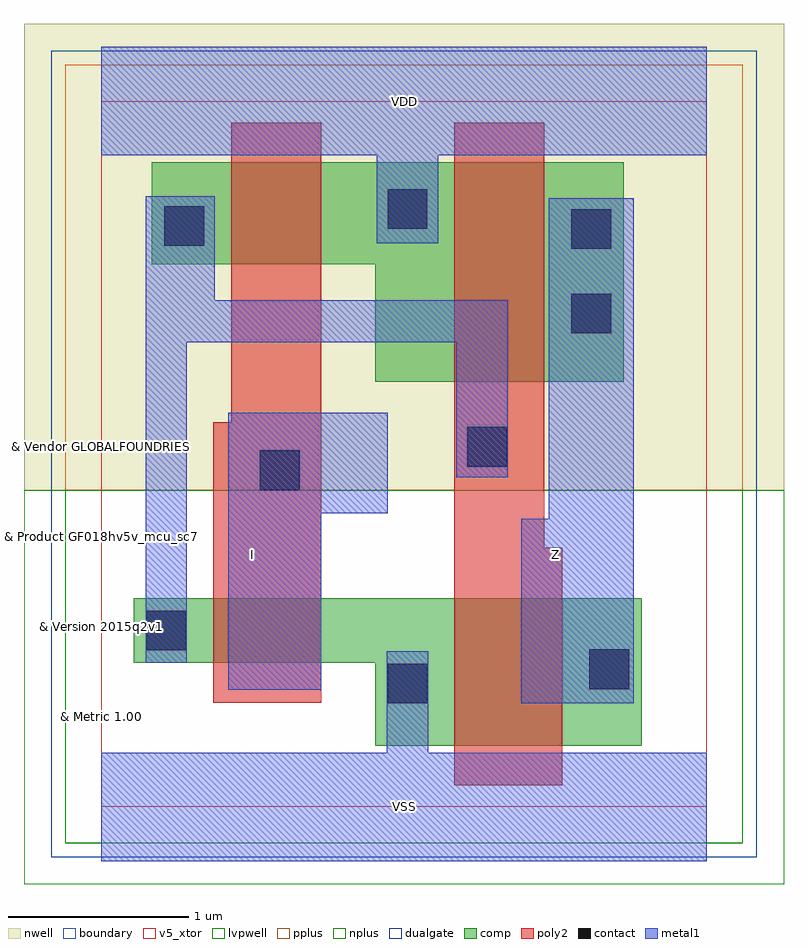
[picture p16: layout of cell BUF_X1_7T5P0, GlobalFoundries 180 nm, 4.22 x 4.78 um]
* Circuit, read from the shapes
.subckt BUF_X1_7T5P0 I VDD VSS Z
XM1 VSS I n1 VSUBS nfet_05v0 w=0.36u l=0.6u
XM2 Z n1 VSS VSUBS nfet_05v0 w=0.82u l=0.6u
XM3 VDD I n1 n2 pfet_05v0 w=0.565u l=0.5u
XM4 Z n1 VDD n2 pfet_05v0 w=1.22u l=0.5u
.ends

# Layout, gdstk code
import gdstk
lib = gdstk.Library(unit=1e-6, precision=1e-09)
def R(c, l, rs):  # rectangles x0, y0, x1, y1
    for r in rs: c.add(gdstk.rectangle(r[:2], r[2:], *l))
def P(c, l, *ps):  # polygons
    for p in ps: c.add(gdstk.Polygon(p, *l))
boundary = (0, 0)
nwell = (21, 0)
comp = (22, 0)
poly2 = (30, 0)
pplus = (31, 0)
nplus = (32, 0)
contact = (33, 0)
metal1 = (34, 0)
dualgate = (55, 0)
v5_xtor = (112, 1)
lvpwell = (204, 0)

buf_x1_7t5p0 = lib.new_cell('BUF_X1_7T5P0')
R(buf_x1_7t5p0, boundary, [(0,0,3.36,3.92)])
R(buf_x1_7t5p0, nwell, [(-0.43,1.76,3.79,4.35)])
P(buf_x1_7t5p0, comp, [(0.28,3.015),(1.52,3.015),(1.52,2.36),(2.9,2.36),(2.9,3.58),(0.28,3.58)],
  [(0.18,0.8),(1.52,0.8),(1.52,0.34),(3,0.34),(3,1.16),(0.18,1.16)])
P(buf_x1_7t5p0, poly2, [(0.62,0.58),(1.22,0.58),(1.22,3.8),(0.72,3.8),(0.72,2.135),(0.62,2.135)],
  [(1.96,0.12),(2.56,0.12),(2.56,1.44),(2.46,1.44),(2.46,3.8),(1.96,3.8)])
R(buf_x1_7t5p0, pplus, [(-0.2,1.76,3.56,4.12)])
R(buf_x1_7t5p0, nplus, [(-0.2,-0.2,3.56,1.76)])
R(buf_x1_7t5p0, contact, [(1.59,0.575,1.81,0.795), (2.71,0.655,2.93,0.875), (0.25,0.87,0.47,1.09), (0.88,1.76,1.1,1.98), (2.03,1.89,2.25,2.11), (2.61,2.63,2.83,2.85), (2.61,3.1,2.83,3.32), (0.35,3.115,0.57,3.335), (1.59,3.21,1.81,3.43)])
P(buf_x1_7t5p0, metal1, [(0.705,0.65),(1.22,0.65),(1.22,1.63),(1.59,1.63),(1.59,2.19),(0.705,2.19)],
  [(0.245,0.8),(0.475,0.8),(0.475,2.58),(1.97,2.58),(1.97,1.83),(2.255,1.83),(2.255,2.815),(0.63,2.815),(0.63,3.39),(0.245,3.39)],
  [(2.33,0.575),(2.955,0.575),(2.955,3.38),(2.485,3.38),(2.485,1.6),(2.33,1.6)],
  [(0,-0.3),(3.36,-0.3),(3.36,0.3),(1.815,0.3),(1.815,0.865),(1.585,0.865),(1.585,0.3),(0,0.3)],
  [(0,3.62),(1.53,3.62),(1.53,3.13),(1.87,3.13),(1.87,3.62),(3.36,3.62),(3.36,4.22),(0,4.22)])
R(buf_x1_7t5p0, dualgate, [(-0.28,-0.28,3.64,4.2)])
R(buf_x1_7t5p0, v5_xtor, [(0,0,3.36,3.92)])
R(buf_x1_7t5p0, lvpwell, [(-0.43,-0.43,3.79,1.76)])
buf_x1_7t5p0.add(gdstk.Label('VSS', (1.68,0), layer=34, texttype=10))
buf_x1_7t5p0.add(gdstk.Label('Z', (2.52,1.4), layer=34, texttype=10))
buf_x1_7t5p0.add(gdstk.Label('I', (0.84,1.4), layer=34, texttype=10))
buf_x1_7t5p0.add(gdstk.Label('VDD', (1.68,3.92), layer=34, texttype=10))
buf_x1_7t5p0.add(gdstk.Label('& Vendor GLOBALFOUNDRIES', (0,2), layer=63, texttype=63))
buf_x1_7t5p0.add(gdstk.Label('& Product GF018hv5v_mcu_sc7', (0,1.5), layer=63, texttype=63))
buf_x1_7t5p0.add(gdstk.Label('& Version 2015q2v1', (0,1), layer=63, texttype=63))
buf_x1_7t5p0.add(gdstk.Label('& Metric 1.00', (0,0.5), layer=63, texttype=63))

lib.write_gds('BUF_X1_7T5P0.gds')
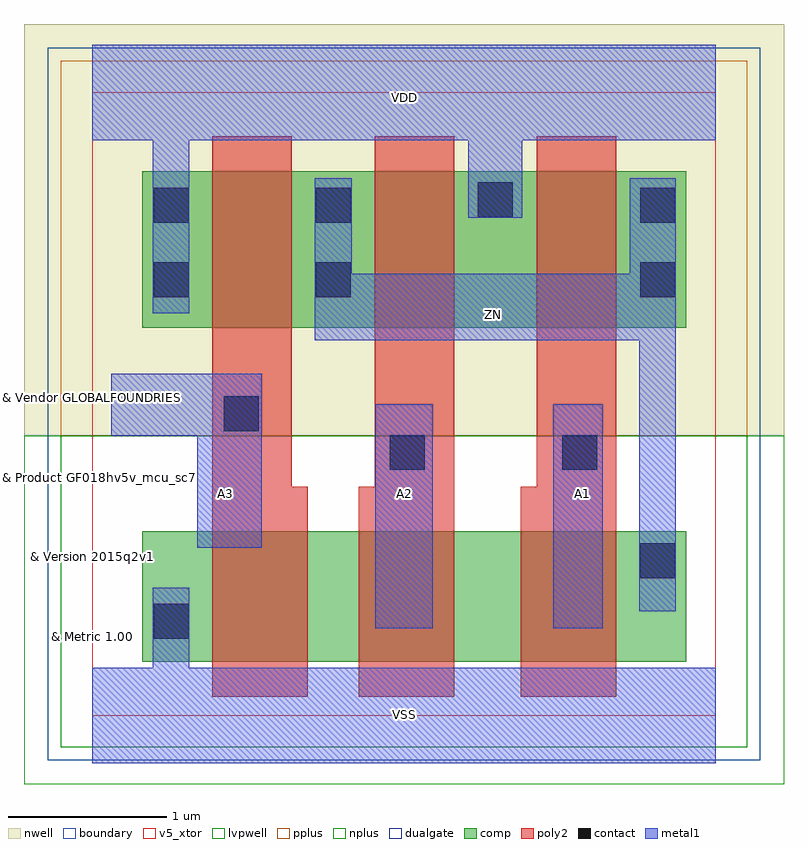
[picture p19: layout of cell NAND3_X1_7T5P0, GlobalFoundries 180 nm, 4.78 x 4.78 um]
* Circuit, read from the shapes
.subckt NAND3_X1_7T5P0 A1 A2 A3 VDD VSS ZN
XM1 n1 A3 VSS VSUBS nfet_05v0 w=0.82u l=0.6u
XM2 n2 A2 n1 VSUBS nfet_05v0 w=0.82u l=0.6u
XM3 ZN A1 n2 VSUBS nfet_05v0 w=0.82u l=0.6u
XM4 ZN A3 VDD n3 pfet_05v0 w=0.985u l=0.5u
XM5 VDD A2 ZN n3 pfet_05v0 w=0.985u l=0.5u
XM6 ZN A1 VDD n3 pfet_05v0 w=0.985u l=0.5u
.ends

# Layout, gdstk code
import gdstk
lib = gdstk.Library(unit=1e-6, precision=1e-09)
def R(c, l, rs):  # rectangles x0, y0, x1, y1
    for r in rs: c.add(gdstk.rectangle(r[:2], r[2:], *l))
def P(c, l, *ps):  # polygons
    for p in ps: c.add(gdstk.Polygon(p, *l))
boundary = (0, 0)
nwell = (21, 0)
comp = (22, 0)
poly2 = (30, 0)
pplus = (31, 0)
nplus = (32, 0)
contact = (33, 0)
metal1 = (34, 0)
dualgate = (55, 0)
v5_xtor = (112, 1)
lvpwell = (204, 0)

nand3_x1_7t5p0 = lib.new_cell('NAND3_X1_7T5P0')
R(nand3_x1_7t5p0, boundary, [(0,0,3.92,3.92)])
R(nand3_x1_7t5p0, nwell, [(-0.43,1.76,4.35,4.35)])
R(nand3_x1_7t5p0, comp, [(0.315,0.34,3.735,1.16), (0.315,2.44,3.735,3.425)])
P(nand3_x1_7t5p0, poly2, [(0.755,0.12),(1.355,0.12),(1.355,1.44),(1.255,1.44),(1.255,3.645),(0.755,3.645)],
  [(1.675,0.12),(2.275,0.12),(2.275,3.645),(1.775,3.645),(1.775,1.44),(1.675,1.44)],
  [(2.695,0.12),(3.295,0.12),(3.295,3.645),(2.795,3.645),(2.795,1.44),(2.695,1.44)])
R(nand3_x1_7t5p0, pplus, [(-0.2,1.76,4.12,4.12)])
R(nand3_x1_7t5p0, nplus, [(-0.2,-0.2,4.12,1.76)])
R(nand3_x1_7t5p0, contact, [(0.385,0.485,0.605,0.705), (3.445,0.865,3.665,1.085), (1.87,1.545,2.09,1.765), (2.955,1.545,3.175,1.765), (0.825,1.79,1.045,2.01), (0.385,2.63,0.605,2.85), (1.405,2.63,1.625,2.85), (3.445,2.63,3.665,2.85), (0.385,3.1,0.605,3.32), (1.405,3.1,1.625,3.32), (3.445,3.1,3.665,3.32), (2.425,3.135,2.645,3.355)])
R(nand3_x1_7t5p0, metal1, [(1.78,0.55,2.14,1.96), (2.9,0.55,3.21,1.96)])
P(nand3_x1_7t5p0, metal1, [(0.12,1.76),(0.66,1.76),(0.66,1.055),(1.065,1.055),(1.065,2.15),(0.12,2.15)],
  [(1.4,2.36),(3.44,2.36),(3.44,0.655),(3.67,0.655),(3.67,3.38),(3.38,3.38),(3.38,2.78),(1.63,2.78),(1.63,3.38),(1.4,3.38)],
  [(0,-0.3),(3.92,-0.3),(3.92,0.3),(0.61,0.3),(0.61,0.805),(0.38,0.805),(0.38,0.3),(0,0.3)],
  [(0,3.62),(0.38,3.62),(0.38,2.53),(0.61,2.53),(0.61,3.62),(2.365,3.62),(2.365,3.13),(2.705,3.13),(2.705,3.62),(3.92,3.62),(3.92,4.22),(0,4.22)])
R(nand3_x1_7t5p0, dualgate, [(-0.28,-0.28,4.2,4.2)])
R(nand3_x1_7t5p0, v5_xtor, [(0,0,3.92,3.92)])
R(nand3_x1_7t5p0, lvpwell, [(-0.43,-0.43,4.35,1.76)])
nand3_x1_7t5p0.add(gdstk.Label('A3', (0.84,1.4), layer=34, texttype=10))
nand3_x1_7t5p0.add(gdstk.Label('VDD', (1.96,3.89), layer=34, texttype=10))
nand3_x1_7t5p0.add(gdstk.Label('VSS', (1.96,0.01), layer=34, texttype=10))
nand3_x1_7t5p0.add(gdstk.Label('ZN', (2.52,2.52), layer=34, texttype=10))
nand3_x1_7t5p0.add(gdstk.Label('A1', (3.08,1.4), layer=34, texttype=10))
nand3_x1_7t5p0.add(gdstk.Label('A2', (1.96,1.4), layer=34, texttype=10))
nand3_x1_7t5p0.add(gdstk.Label('& Vendor GLOBALFOUNDRIES', (0,2), layer=63, texttype=63))
nand3_x1_7t5p0.add(gdstk.Label('& Product GF018hv5v_mcu_sc7', (0,1.5), layer=63, texttype=63))
nand3_x1_7t5p0.add(gdstk.Label('& Version 2015q2v1', (0,1), layer=63, texttype=63))
nand3_x1_7t5p0.add(gdstk.Label('& Metric 1.00', (0,0.5), layer=63, texttype=63))

lib.write_gds('NAND3_X1_7T5P0.gds')
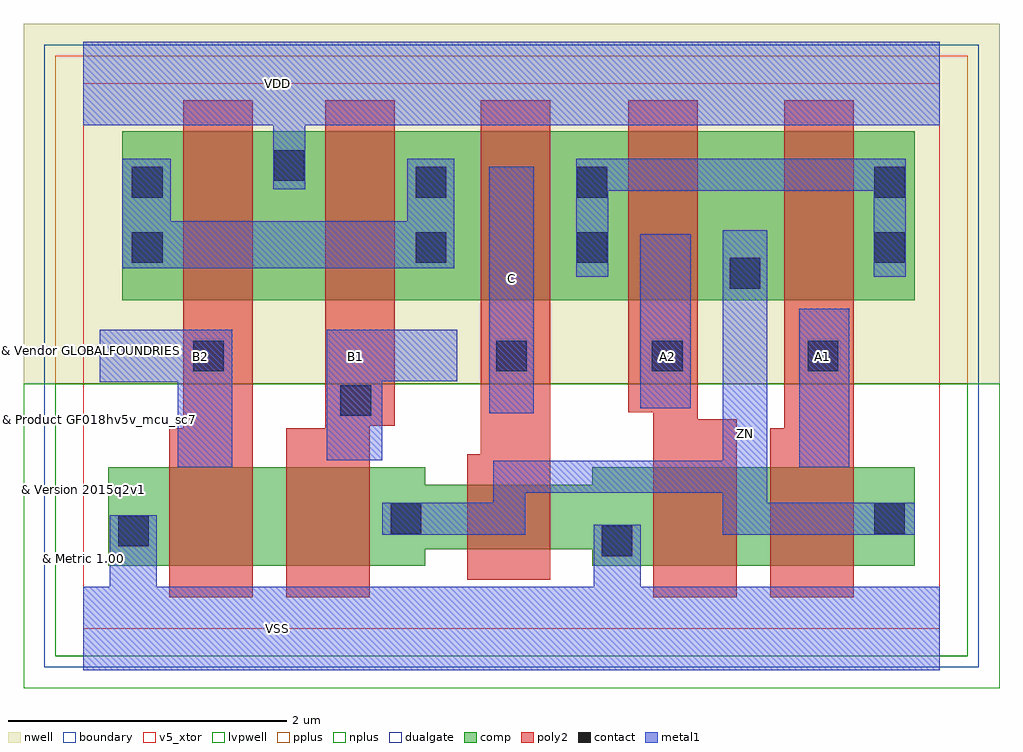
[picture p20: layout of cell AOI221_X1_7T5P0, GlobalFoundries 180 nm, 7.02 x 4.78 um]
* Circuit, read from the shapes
.subckt AOI221_X1_7T5P0 A1 A2 B1 B2 C VDD VSS ZN
XM1 n1 B2 VSS VSUBS nfet_05v0 w=0.71u l=0.6u
XM2 ZN B1 n1 VSUBS nfet_05v0 w=0.71u l=0.6u
XM3 VSS C ZN VSUBS nfet_05v0 w=0.465u l=0.6u
XM4 n2 A2 VSS VSUBS nfet_05v0 w=0.71u l=0.6u
XM5 ZN A1 n2 VSUBS nfet_05v0 w=0.71u l=0.6u
XM6 VDD B2 n3 n4 pfet_05v0 w=1.215u l=0.5u
XM7 n3 B1 VDD n4 pfet_05v0 w=1.215u l=0.5u
XM8 n5 C n3 n4 pfet_05v0 w=1.215u l=0.5u
XM9 ZN A2 n5 n4 pfet_05v0 w=1.215u l=0.5u
XM10 n5 A1 ZN n4 pfet_05v0 w=1.215u l=0.5u
.ends

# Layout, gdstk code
import gdstk
lib = gdstk.Library(unit=1e-6, precision=1e-09)
def R(c, l, rs):  # rectangles x0, y0, x1, y1
    for r in rs: c.add(gdstk.rectangle(r[:2], r[2:], *l))
def A(c, l, x, y, w, h, nx, ny, dx, dy):  # array of equal rectangles
    R(c, l, [(x+i*dx, y+j*dy, x+i*dx+w, y+j*dy+h) for i in range(nx) for j in range(ny)])
def P(c, l, *ps):  # polygons
    for p in ps: c.add(gdstk.Polygon(p, *l))
boundary = (0, 0)
nwell = (21, 0)
comp = (22, 0)
poly2 = (30, 0)
pplus = (31, 0)
nplus = (32, 0)
contact = (33, 0)
metal1 = (34, 0)
dualgate = (55, 0)
v5_xtor = (112, 1)
lvpwell = (204, 0)

aoi221_x1_7t5p0 = lib.new_cell('AOI221_X1_7T5P0')
R(aoi221_x1_7t5p0, boundary, [(0,0,6.16,3.92)])
R(aoi221_x1_7t5p0, nwell, [(-0.43,1.76,6.59,4.35)])
R(aoi221_x1_7t5p0, comp, [(0.28,2.36,5.98,3.575)])
P(aoi221_x1_7t5p0, comp, [(0.18,0.45),(2.46,0.45),(2.46,0.57),(3.66,0.57),(3.66,0.45),(5.98,0.45),(5.98,1.16),(3.66,1.16),(3.66,1.035),(2.46,1.035),(2.46,1.16),(0.18,1.16)])
P(aoi221_x1_7t5p0, poly2, [(0.62,0.225),(1.22,0.225),(1.22,3.8),(0.72,3.8),(0.72,1.44),(0.62,1.44)],
  [(1.46,0.225),(2.06,0.225),(2.06,1.46),(2.24,1.46),(2.24,3.8),(1.74,3.8),(1.74,1.44),(1.46,1.44)],
  [(2.76,0.35),(3.36,0.35),(3.36,3.8),(2.86,3.8),(2.86,1.255),(2.76,1.255)],
  [(3.92,1.555),(4.1,1.555),(4.1,0.225),(4.7,0.225),(4.7,1.505),(4.42,1.505),(4.42,3.8),(3.92,3.8)],
  [(4.94,0.225),(5.54,0.225),(5.54,3.8),(5.04,3.8),(5.04,1.44),(4.94,1.44)])
R(aoi221_x1_7t5p0, pplus, [(-0.2,1.76,6.36,4.12)])
R(aoi221_x1_7t5p0, nplus, [(-0.2,-0.2,6.36,1.76)])
A(aoi221_x1_7t5p0, contact, 2.97, 1.85, 0.22, 0.22, 3, 1, 1.12, 0)
R(aoi221_x1_7t5p0, contact, [(3.73,0.52,3.95,0.74), (0.25,0.59,0.47,0.81), (2.21,0.68,2.43,0.9), (5.69,0.68,5.91,0.9), (1.85,1.53,2.07,1.75), (0.79,1.85,1.01,2.07), (4.65,2.445,4.87,2.665), (0.35,2.63,0.57,2.85), (2.39,2.63,2.61,2.85), (3.55,2.63,3.77,2.85), (5.69,2.63,5.91,2.85), (0.35,3.1,0.57,3.32), (2.39,3.1,2.61,3.32), (3.55,3.1,3.77,3.32), (5.69,3.1,5.91,3.32), (1.37,3.22,1.59,3.44)])
R(aoi221_x1_7t5p0, metal1, [(5.15,1.16,5.51,2.3), (2.92,1.55,3.24,3.32), (4.005,1.585,4.37,2.835)])
P(aoi221_x1_7t5p0, metal1, [(0.12,1.77),(0.68,1.77),(0.68,1.16),(1.07,1.16),(1.07,2.15),(0.12,2.15)],
  [(0.28,2.59),(2.67,2.59),(2.67,3.38),(2.33,3.38),(2.33,2.93),(0.63,2.93),(0.63,3.38),(0.28,3.38)],
  [(1.75,1.21),(2.15,1.21),(2.15,1.78),(2.69,1.78),(2.69,2.15),(1.75,2.15)],
  [(3.545,2.53),(3.775,2.53),(3.775,3.15),(5.685,3.15),(5.685,2.53),(5.915,2.53),(5.915,3.38),(3.545,3.38)],
  [(2.15,0.675),(3.18,0.675),(3.18,0.975),(4.6,0.975),(4.6,0.675),(5.98,0.675),(5.98,0.905),(4.92,0.905),(4.92,2.865),(4.6,2.865),(4.6,1.205),(2.95,1.205),(2.95,0.905),(2.15,0.905)],
  [(0,-0.3),(6.16,-0.3),(6.16,0.3),(4.01,0.3),(4.01,0.745),(3.67,0.745),(3.67,0.3),(0.53,0.3),(0.53,0.815),(0.19,0.815),(0.19,0.3),(0,0.3)],
  [(0,3.62),(1.365,3.62),(1.365,3.16),(1.595,3.16),(1.595,3.62),(6.16,3.62),(6.16,4.22),(0,4.22)])
R(aoi221_x1_7t5p0, dualgate, [(-0.28,-0.28,6.44,4.2)])
R(aoi221_x1_7t5p0, v5_xtor, [(0,0,6.16,3.92)])
R(aoi221_x1_7t5p0, lvpwell, [(-0.43,-0.43,6.59,1.76)])
aoi221_x1_7t5p0.add(gdstk.Label('B2', (0.84,1.96), layer=34, texttype=10))
aoi221_x1_7t5p0.add(gdstk.Label('C', (3.08,2.52), layer=34, texttype=10))
aoi221_x1_7t5p0.add(gdstk.Label('VDD', (1.4,3.92), layer=34, texttype=10))
aoi221_x1_7t5p0.add(gdstk.Label('VSS', (1.4,0), layer=34, texttype=10))
aoi221_x1_7t5p0.add(gdstk.Label('ZN', (4.76,1.4), layer=34, texttype=10))
aoi221_x1_7t5p0.add(gdstk.Label('A1', (5.32,1.96), layer=34, texttype=10))
aoi221_x1_7t5p0.add(gdstk.Label('A2', (4.2,1.96), layer=34, texttype=10))
aoi221_x1_7t5p0.add(gdstk.Label('B1', (1.96,1.96), layer=34, texttype=10))
aoi221_x1_7t5p0.add(gdstk.Label('& Vendor GLOBALFOUNDRIES', (0,2), layer=63, texttype=63))
aoi221_x1_7t5p0.add(gdstk.Label('& Product GF018hv5v_mcu_sc7', (0,1.5), layer=63, texttype=63))
aoi221_x1_7t5p0.add(gdstk.Label('& Version 2015q2v1', (0,1), layer=63, texttype=63))
aoi221_x1_7t5p0.add(gdstk.Label('& Metric 1.00', (0,0.5), layer=63, texttype=63))

lib.write_gds('AOI221_X1_7T5P0.gds')
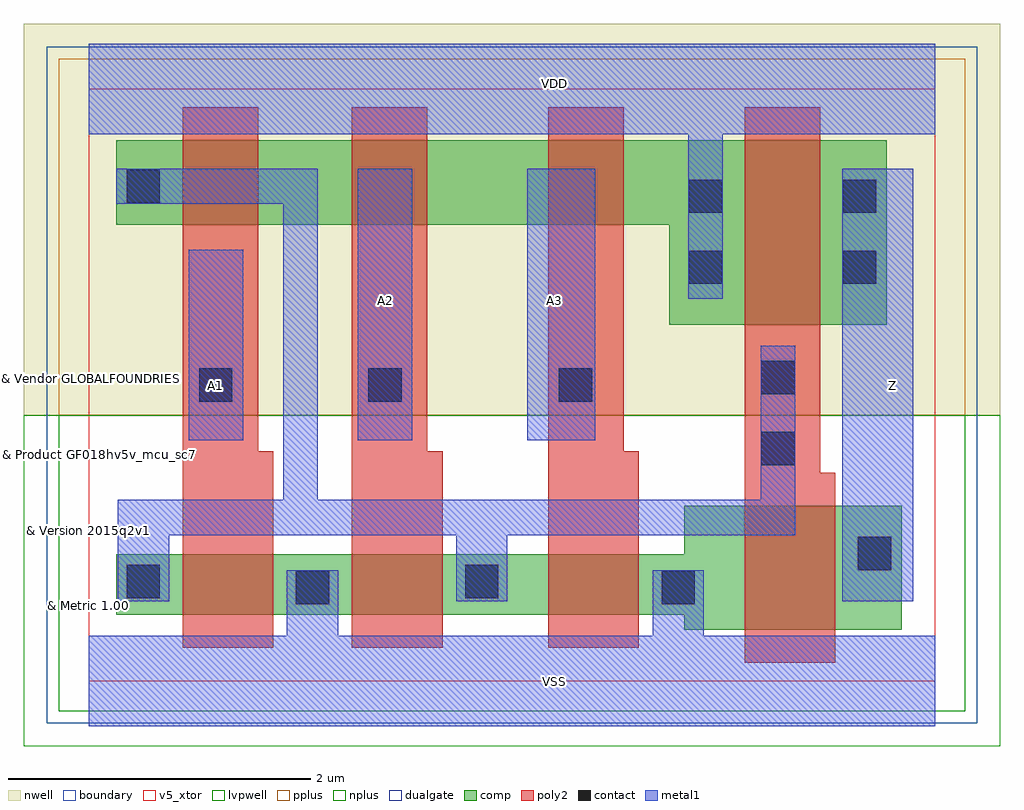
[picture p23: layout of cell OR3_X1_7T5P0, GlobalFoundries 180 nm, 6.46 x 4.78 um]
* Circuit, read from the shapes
.subckt OR3_X1_7T5P0 A1 A2 A3 VDD VSS Z
XM1 VSS A1 n1 VSUBS nfet_05v0 w=0.4u l=0.6u
XM2 n1 A2 VSS VSUBS nfet_05v0 w=0.4u l=0.6u
XM3 VSS A3 n1 VSUBS nfet_05v0 w=0.4u l=0.6u
XM4 Z n1 VSS VSUBS nfet_05v0 w=0.82u l=0.6u
XM5 n2 A1 n1 n3 pfet_05v0 w=0.56u l=0.5u
XM6 n4 A2 n2 n3 pfet_05v0 w=0.56u l=0.5u
XM7 VDD A3 n4 n3 pfet_05v0 w=0.56u l=0.5u
XM8 Z n1 VDD n3 pfet_05v0 w=1.22u l=0.5u
.ends

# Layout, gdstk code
import gdstk
lib = gdstk.Library(unit=1e-6, precision=1e-09)
def R(c, l, rs):  # rectangles x0, y0, x1, y1
    for r in rs: c.add(gdstk.rectangle(r[:2], r[2:], *l))
def P(c, l, *ps):  # polygons
    for p in ps: c.add(gdstk.Polygon(p, *l))
boundary = (0, 0)
nwell = (21, 0)
comp = (22, 0)
poly2 = (30, 0)
pplus = (31, 0)
nplus = (32, 0)
contact = (33, 0)
metal1 = (34, 0)
dualgate = (55, 0)
v5_xtor = (112, 1)
lvpwell = (204, 0)

or3_x1_7t5p0 = lib.new_cell('OR3_X1_7T5P0')
R(or3_x1_7t5p0, boundary, [(0,0,5.6,3.92)])
R(or3_x1_7t5p0, nwell, [(-0.43,1.76,6.03,4.35)])
P(or3_x1_7t5p0, comp, [(0.18,3.02),(3.84,3.02),(3.84,2.36),(5.28,2.36),(5.28,3.58),(0.18,3.58)],
  [(0.18,0.44),(3.94,0.44),(3.94,0.34),(5.38,0.34),(5.38,1.16),(3.94,1.16),(3.94,0.84),(0.18,0.84)])
P(or3_x1_7t5p0, poly2, [(0.62,0.22),(1.22,0.22),(1.22,1.52),(1.12,1.52),(1.12,3.8),(0.62,3.8)],
  [(1.74,0.22),(2.34,0.22),(2.34,1.52),(2.24,1.52),(2.24,3.8),(1.74,3.8)],
  [(3.04,0.22),(3.64,0.22),(3.64,1.52),(3.54,1.52),(3.54,3.8),(3.04,3.8)],
  [(4.34,0.12),(4.94,0.12),(4.94,1.38),(4.84,1.38),(4.84,3.8),(4.34,3.8)])
R(or3_x1_7t5p0, pplus, [(-0.2,1.76,5.8,4.12)])
R(or3_x1_7t5p0, nplus, [(-0.2,-0.2,5.8,1.76)])
R(or3_x1_7t5p0, contact, [(1.37,0.51,1.59,0.73), (3.79,0.51,4.01,0.73), (0.25,0.55,0.47,0.77), (2.49,0.55,2.71,0.77), (5.09,0.735,5.31,0.955), (4.45,1.43,4.67,1.65), (0.73,1.85,0.95,2.07), (1.85,1.85,2.07,2.07), (3.11,1.85,3.33,2.07), (4.45,1.9,4.67,2.12), (3.97,2.63,4.19,2.85), (4.99,2.63,5.21,2.85), (3.97,3.1,4.19,3.32), (4.99,3.1,5.21,3.32), (0.25,3.165,0.47,3.385)])
R(or3_x1_7t5p0, metal1, [(4.985,0.53,5.455,3.39), (0.66,1.595,1.02,2.855), (1.78,1.595,2.14,3.39), (2.9,1.595,3.35,3.39)])
P(or3_x1_7t5p0, metal1, [(0.18,3.16),(1.285,3.16),(1.285,1.2),(0.19,1.2),(0.19,0.53),(0.53,0.53),(0.53,0.965),(2.43,0.965),(2.43,0.53),(2.77,0.53),(2.77,0.965),(4.675,0.965),(4.675,2.22),(4.445,2.22),(4.445,1.2),(1.515,1.2),(1.515,3.39),(0.18,3.39)],
  [(0,-0.3),(5.6,-0.3),(5.6,0.3),(4.07,0.3),(4.07,0.735),(3.73,0.735),(3.73,0.3),(1.65,0.3),(1.65,0.735),(1.31,0.735),(1.31,0.3),(0,0.3)],
  [(0,3.62),(3.965,3.62),(3.965,2.53),(4.195,2.53),(4.195,3.62),(5.6,3.62),(5.6,4.22),(0,4.22)])
R(or3_x1_7t5p0, dualgate, [(-0.28,-0.28,5.88,4.2)])
R(or3_x1_7t5p0, v5_xtor, [(0,0,5.6,3.92)])
R(or3_x1_7t5p0, lvpwell, [(-0.43,-0.43,6.03,1.76)])
or3_x1_7t5p0.add(gdstk.Label('A3', (3.08,2.52), layer=34, texttype=10))
or3_x1_7t5p0.add(gdstk.Label('VDD', (3.08,3.955), layer=34, texttype=10))
or3_x1_7t5p0.add(gdstk.Label('VSS', (3.08,-0.005), layer=34, texttype=10))
or3_x1_7t5p0.add(gdstk.Label('Z', (5.32,1.96), layer=34, texttype=10))
or3_x1_7t5p0.add(gdstk.Label('A1', (0.84,1.96), layer=34, texttype=10))
or3_x1_7t5p0.add(gdstk.Label('A2', (1.96,2.52), layer=34, texttype=10))
or3_x1_7t5p0.add(gdstk.Label('& Vendor GLOBALFOUNDRIES', (0,2), layer=63, texttype=63))
or3_x1_7t5p0.add(gdstk.Label('& Product GF018hv5v_mcu_sc7', (0,1.5), layer=63, texttype=63))
or3_x1_7t5p0.add(gdstk.Label('& Version 2015q2v1', (0,1), layer=63, texttype=63))
or3_x1_7t5p0.add(gdstk.Label('& Metric 1.00', (0,0.5), layer=63, texttype=63))

lib.write_gds('OR3_X1_7T5P0.gds')
